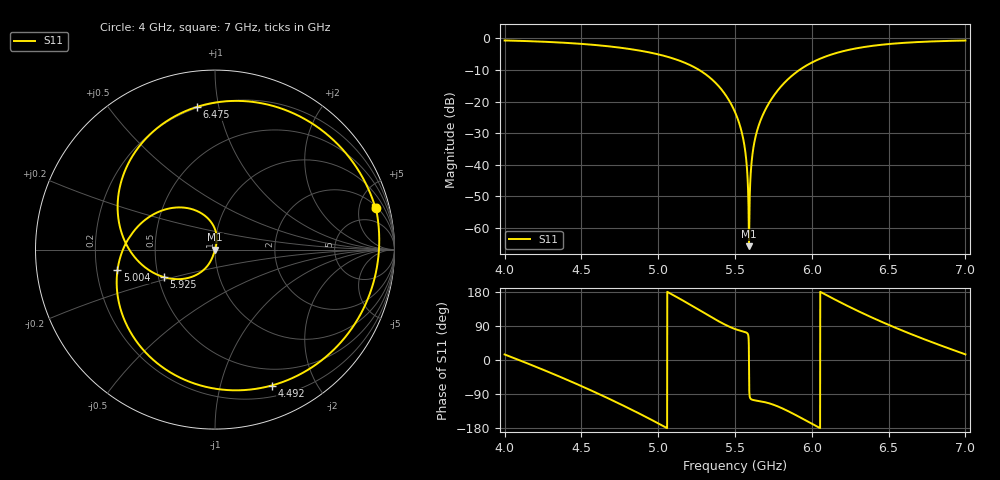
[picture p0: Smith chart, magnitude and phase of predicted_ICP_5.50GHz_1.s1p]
! ICP-predicted S11, target max centred GHz at -10 dB. Complex ensemble mean (passive and causal);
! its |S11| can differ slightly from the dB-domain mean reported in designs.csv.
!  Air_gap = 4.46mm
!  W_Patch = 17.27mm
!  L_Patch = 17.88mm
!  Sx = 2.02mm
!  Sy = 3.77mm
!  W_Patch1 = 11.2mm
!  WS = 1.18mm
!  Curve_Amp1 = 0.96mm
!  Extra = 4.1mm
# GHz S MA R 50
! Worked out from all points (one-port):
!   3001 points, 4 GHz to 7 GHz, reference 50 ohm
!   lowest |S11| = -65.7 dB at 5.591 GHz (marker M1), VSWR 1.00, Z = 50.1 - j0.00535 ohm
!   |S11| at or under -10 dB: 5.267 GHz to 5.92 GHz (652.9 MHz wide, 11.7 % of centre)
!   S11 on the Smith chart (normalised r, x): 4 GHz: 2.17, +7.14; 4.492 GHz: 0.31, -1.45; 5.004 GHz: 0.29, -0.10; 5.925 GHz: 0.54, -0.18; 6.475 GHz: 0.19, +0.86; 7 GHz: 2.16, +6.98
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4  0.9261 14.6
4.185  0.8981 -14.9
4.375  0.8554 -46.8
4.492  0.8203 -67.4
4.62  0.7728 -90.9
4.75  0.713 -115.9
4.882  0.6385 -142.3
5.004  0.5554 -168.1
5.125  0.4559 165.2
5.353  0.2207 111.5
5.5  0.06822 81.8
5.555  0.02464 75.0
5.57  0.01414 73.0
5.581  0.006721 70.1
5.591  0.0005168 -5.9
5.601  0.006451 -102.0
5.612  0.01357 -104.8
5.624  0.02138 -106.1
5.666  0.0501 -108.9
5.753  0.1244 -118.4
5.875  0.2616 -140.9
5.925  0.323 -151.6
6.103  0.5299 169.6
6.25  0.665 139.2
6.475  0.8017 97.1
6.625  0.8566 71.8
6.826  0.9015 40.4
7  0.9236 14.9
